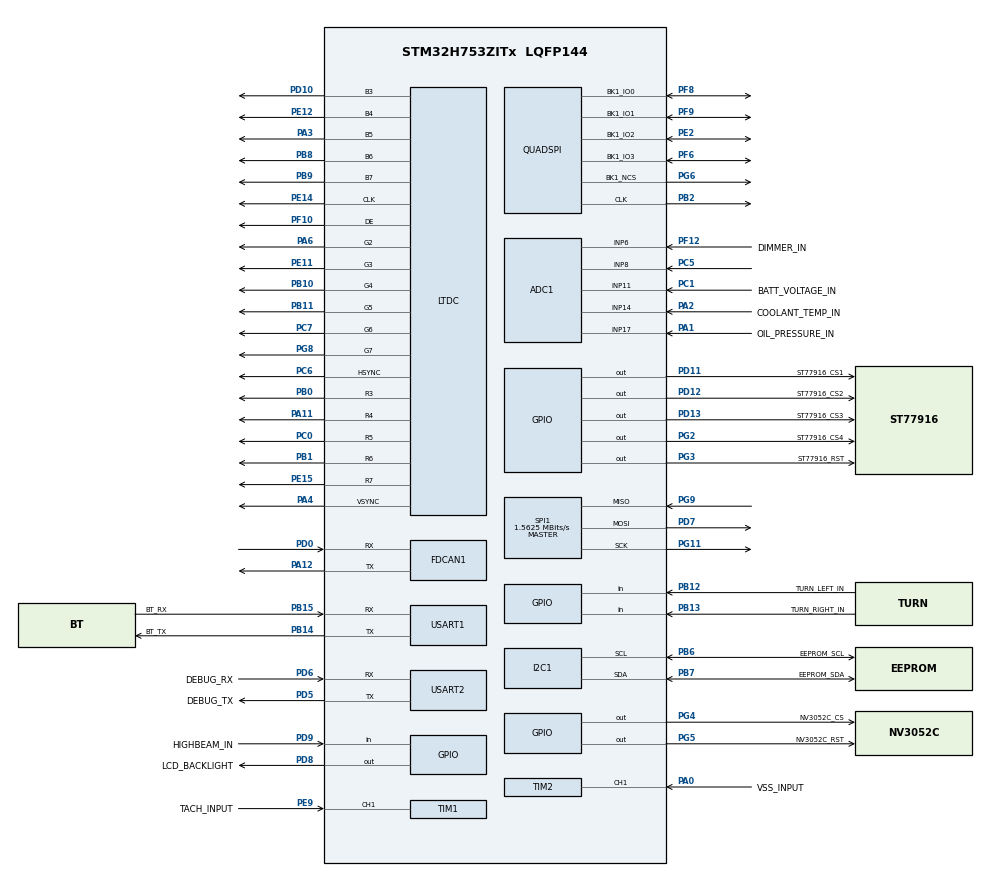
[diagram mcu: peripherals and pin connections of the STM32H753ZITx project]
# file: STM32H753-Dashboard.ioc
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ADC1.Channel-0\#ChannelRegularConversion=ADC_CHANNEL_6
ADC1.NbrOfConversionFlag=1
ADC1.OffsetNumber-0\#ChannelRegularConversion=ADC_OFFSET_NONE
ADC1.OffsetSignedSaturation-0\#ChannelRegularConversion=DISABLE
ADC1.Rank-0\#ChannelRegularConversion=1
ADC1.SamplingTime-0\#ChannelRegularConversion=ADC_SAMPLETIME_1CYCLE_5
ADC1.master=1
CORTEX_M7.default_mode_Activation=1
FDCAN1.AutoRetransmission=ENABLE
FDCAN1.CalculateBaudRateNominal=1000000
FDCAN1.CalculateTimeBitNominal=1000
FDCAN1.CalculateTimeQuantumNominal=100.0
FDCAN1.NominalPrescaler=5
FDCAN1.NominalTimeSeg1=7
FDCAN1.NominalTimeSeg2=2
FDCAN1.RxFifo0ElmtsNbr=8
FDCAN1.TxFifoQueueElmtsNbr=32
I2C1.Timing=0x00707CBB
LTDC.ActiveH=720
LTDC.ActiveW=720
LTDC.HBP=44
LTDC.HFP=46
LTDC.HSync=2
LTDC.Layers=0
LTDC.PixelFormat_L0=LTDC_PIXEL_FORMAT_RGB565
LTDC.VBP=16
LTDC.VFP=50
LTDC.VSync=5
LTDC.WindowX1_L0=719
LTDC.WindowY1_L0=719
Mcu.Family=STM32H7
Mcu.Name=STM32H753ZITx
Mcu.Package=LQFP144
NVIC.PriorityGroup=NVIC_PRIORITYGROUP_4
NVIC.TIM6_DAC_IRQn=true\:0\:0\:false\:false\:true\:true\:true\:true
PA0.GPIO_Label=VSS_INPUT
PA0.Signal=S_TIM2_CH1_ETR
PA1.GPIO_Label=OIL_PRESSURE_IN
PA1.Mode=IN17-Single-Ended
PA1.Signal=ADC1_INP17
PA11.Mode=RGB565
PA11.Signal=LTDC_R4
PA12.Mode=FDCAN_Activate
PA12.Signal=FDCAN1_TX
PA2.GPIO_Label=COOLANT_TEMP_IN
PA2.Signal=ADCx_INP14
PA3.Mode=RGB565
PA3.Signal=LTDC_B5
PA4.Mode=RGB565
PA4.Signal=LTDC_VSYNC
PA6.Mode=RGB565
PA6.Signal=LTDC_G2
PB0.Mode=RGB565
PB0.Signal=LTDC_R3
PB1.Mode=RGB565
PB1.Signal=LTDC_R6
PB10.Mode=RGB565
PB10.Signal=LTDC_G4
PB11.Mode=RGB565
PB11.Signal=LTDC_G5
PB12.GPIO_Label=TURN_LEFT_IN
PB12.Signal=GPIO_Input
PB13.GPIO_Label=TURN_RIGHT_IN
PB13.Signal=GPIO_Input
PB14.GPIO_Label=BT_TX
PB14.Mode=Asynchronous
PB14.Signal=USART1_TX
PB15.GPIO_Label=BT_RX
PB15.Mode=Asynchronous
PB15.Signal=USART1_RX
PB2.Mode=Single Bank 1
PB2.Signal=QUADSPI_CLK
PB6.GPIO_Label=EEPROM_SCL
PB6.Mode=I2C
PB6.Signal=I2C1_SCL
PB7.GPIO_Label=EEPROM_SDA
PB7.Mode=I2C
PB7.Signal=I2C1_SDA
PB8.Mode=RGB565
PB8.Signal=LTDC_B6
PB9.Mode=RGB565
PB9.Signal=LTDC_B7
PC0.Mode=RGB565
PC0.Signal=LTDC_R5
PC1.GPIO_Label=BATT_VOLTAGE_IN
PC1.Signal=ADCx_INP11
PC5.Signal=ADCx_INP8
PC6.Mode=RGB565
PC6.Signal=LTDC_HSYNC
PC7.Mode=RGB565
PC7.Signal=LTDC_G6
PD0.Mode=FDCAN_Activate
PD0.Signal=FDCAN1_RX
PD10.Mode=RGB565
PD10.Signal=LTDC_B3
PD11.GPIO_Label=ST77916_CS1
PD11.Signal=GPIO_Output
PD12.GPIO_Label=ST77916_CS2
PD12.Signal=GPIO_Output
PD13.GPIO_Label=ST77916_CS3
PD13.Signal=GPIO_Output
PD5.GPIO_Label=DEBUG_TX
PD5.Mode=Asynchronous
PD5.Signal=USART2_TX
PD6.GPIO_Label=DEBUG_RX
PD6.Mode=Asynchronous
PD6.Signal=USART2_RX
PD7.Mode=Full_Duplex_Master
PD7.Signal=SPI1_MOSI
PD8.GPIO_Label=LCD_BACKLIGHT
PD8.Signal=GPIO_Output
PD9.GPIO_Label=HIGHBEAM_IN
PD9.Signal=GPIO_Input
PE11.Mode=RGB565
PE11.Signal=LTDC_G3
PE12.Mode=RGB565
PE12.Signal=LTDC_B4
PE14.Mode=RGB565
PE14.Signal=LTDC_CLK
PE15.Mode=RGB565
PE15.Signal=LTDC_R7
PE2.Mode=Single Bank 1
PE2.Signal=QUADSPI_BK1_IO2
PE9.GPIO_Label=TACH_INPUT
PE9.Signal=S_TIM1_CH1
PF10.Mode=RGB565
PF10.Signal=LTDC_DE
PF12.GPIO_Label=DIMMER_IN
PF12.Mode=IN6-Single-Ended
PF12.Signal=ADC1_INP6
PF6.Mode=Single Bank 1
PF6.Signal=QUADSPI_BK1_IO3
PF8.Mode=Single Bank 1
PF8.Signal=QUADSPI_BK1_IO0
PF9.Mode=Single Bank 1
PF9.Signal=QUADSPI_BK1_IO1
PG11.Mode=Full_Duplex_Master
PG11.Signal=SPI1_SCK
PG2.GPIO_Label=ST77916_CS4
PG2.Signal=GPIO_Output
PG3.GPIO_Label=ST77916_RST
PG3.Signal=GPIO_Output
PG4.GPIO_Label=NV3052C_CS
PG4.Signal=GPIO_Output
PG5.GPIO_Label=NV3052C_RST
PG5.Signal=GPIO_Output
PG6.Mode=Single Bank 1
PG6.Signal=QUADSPI_BK1_NCS
PG8.Mode=RGB565
PG8.Signal=LTDC_G7
PG9.Mode=Full_Duplex_Master
PG9.Signal=SPI1_MISO
ProjectManager.HeapSize=0x200
ProjectManager.StackSize=0x400
ProjectManager.TargetToolchain=CMake
QUADSPI.ChipSelectHighTime=QSPI_CS_HIGH_TIME_2_CYCLE
QUADSPI.ClockPrescaler=4
QUADSPI.FifoThreshold=4
QUADSPI.FlashSize=22
QUADSPI.SampleShifting=QSPI_SAMPLE_SHIFTING_HALFCYCLE
RCC.ADCFreq_Value=80000000
RCC.APB1Freq_Value=32000000
RCC.APB2Freq_Value=32000000
RCC.APB3Freq_Value=64000000
RCC.APB4Freq_Value=64000000
RCC.CortexFreq_Value=64000000
RCC.D2PPRE1=RCC_APB1_DIV2
RCC.D2PPRE2=RCC_APB2_DIV2
RCC.DIVM1=4
RCC.DIVM2=4
RCC.DIVM3=1
RCC.DIVN1=9
RCC.DIVN2=10
RCC.DIVN3=4
RCC.DIVQ1=3
RCC.DIVR3=6
RCC.HCLKFreq_Value=64000000
RCC.PLL2FRACN=0
RCC.PLL3FRACN=0
RCC.PLLFRACN=3072
RCC.SYSCLKFreq_VALUE=64000000
RCC.USBFreq_Value=50000000
SH.ADCx_INP11.0=ADC1_INP11,IN11-Single-Ended
SH.ADCx_INP14.0=ADC1_INP14,IN14-Single-Ended
SH.ADCx_INP8.0=ADC1_INP8,IN8-Single-Ended
SH.S_TIM1_CH1.0=TIM1_CH1,Input_Capture1_from_TI1
SH.S_TIM2_CH1_ETR.0=TIM2_CH1,Input_Capture1_from_TI1
SPI1.BaudRatePrescaler=SPI_BAUDRATEPRESCALER_32
SPI1.CalculateBaudRate=1.5625 MBits/s
SPI1.DataSize=SPI_DATASIZE_8BIT
SPI1.Direction=SPI_DIRECTION_2LINES
SPI1.Mode=SPI_MODE_MASTER
SPI1.VirtualType=VM_MASTER
TIM1.Channel-Input_Capture1_from_TI1=TIM_CHANNEL_1
TIM2.Channel-Input_Capture1_from_TI1=TIM_CHANNEL_1
TIM6.Period=999
TIM6.Prescaler=63
USART1.VirtualMode-Asynchronous=VM_ASYNC
USART2.VirtualMode-Asynchronous=VM_ASYNC
VP_DMA2D_VS_DMA2D.Mode=DMA2D_Activate
VP_MEMORYMAP_VS_MEMORYMAP.Mode=CurAppReg
VP_TIM1_VS_ClockSourceINT.Mode=Internal
VP_TIM6_VS_ClockSourceINT.Mode=Enable_Timer
board=custom

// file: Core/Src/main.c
/* USER CODE BEGIN Header */
/**
  ******************************************************************************
  * @file           : main.c
  * @brief          : Main program body
  ******************************************************************************
  * @attention
  *
  * Copyright (c) 2026 STMicroelectronics.
  * All rights reserved.
  *
  * This software is licensed under terms that can be found in the LICENSE file
  * in the root directory of this software component.
  * If no LICENSE file comes with this software, it is provided AS-IS.
  *
  ******************************************************************************
  */
/* USER CODE END Header */
#include "main.h"

/* USER CODE BEGIN Includes */
#include "st77916.h"
#include "nv3052c.h"
#include "holley_can.h"
#include "sensors.h"
#include "inputs.h"
#include "config.h"
/* USER CODE END Includes */

ADC_HandleTypeDef hadc1;

DMA2D_HandleTypeDef hdma2d;

FDCAN_HandleTypeDef hfdcan1;

I2C_HandleTypeDef hi2c1;

LTDC_HandleTypeDef hltdc;

QSPI_HandleTypeDef hqspi;

SPI_HandleTypeDef hspi1;

TIM_HandleTypeDef htim1;
TIM_HandleTypeDef htim2;
TIM_HandleTypeDef htim6;

UART_HandleTypeDef huart1;
UART_HandleTypeDef huart2;

void SystemClock_Config(void);
static void MPU_Config(void);
static void MX_GPIO_Init(void);
static void MX_ADC1_Init(void);
static void MX_DMA2D_Init(void);
static void MX_FDCAN1_Init(void);
static void MX_I2C1_Init(void);
static void MX_LTDC_Init(void);
static void MX_QUADSPI_Init(void);
static void MX_SPI1_Init(void);
static void MX_TIM1_Init(void);
static void MX_TIM2_Init(void);
static void MX_TIM6_Init(void);
static void MX_USART1_UART_Init(void);
static void MX_USART2_UART_Init(void);

int main(void)
{

  /* MPU Configuration--------------------------------------------------------*/
  MPU_Config();

  /* MCU Configuration--------------------------------------------------------*/

  /* Reset of all peripherals, Initializes the Flash interface and the Systick. */
  HAL_Init();

  /* USER CODE BEGIN Init */
  /* Framebuffer RAM (AXI SRAM) as write-through: CPU writes reach RAM
   * immediately and in order, so LTDC scanout never sees stale or
   * half-flushed pixels and no per-frame cache maintenance is needed.
   * With write-back this raced the scanline and tore the moving needle.
   * Region 0 (background) is CubeMX-generated; this stacks region 1. */
  {
    MPU_Region_InitTypeDef r = {0};
    HAL_MPU_Disable();
    r.Enable           = MPU_REGION_ENABLE;
    r.Number           = MPU_REGION_NUMBER1;
    r.BaseAddress      = 0x24000000U;
    r.Size             = MPU_REGION_SIZE_512KB;
    r.TypeExtField     = MPU_TEX_LEVEL0;          /* TEX=0, C=1, B=0 = write-through */
    r.AccessPermission = MPU_REGION_FULL_ACCESS;
    r.DisableExec      = MPU_INSTRUCTION_ACCESS_DISABLE;
    r.IsShareable      = MPU_ACCESS_NOT_SHAREABLE;
    r.IsCacheable      = MPU_ACCESS_CACHEABLE;
    r.IsBufferable     = MPU_ACCESS_NOT_BUFFERABLE;
    HAL_MPU_ConfigRegion(&r);
    HAL_MPU_Enable(MPU_PRIVILEGED_DEFAULT);
  }
  /* CPU caches were never enabled; the Cortex-M7 is crippled without them and
   * cache-maintenance ops (used for LTDC framebuffer coherence) hard-fault if
   * executed while the D-cache is off. MPU_Config() has already run. */
  SCB_EnableICache();
  SCB_EnableDCache();
  /* USER CODE END Init */

  /* Configure the system clock */
  SystemClock_Config();

  /* Initialize all configured peripherals */
  MX_GPIO_Init();
  MX_ADC1_Init();
  MX_DMA2D_Init();
  MX_FDCAN1_Init();
  MX_I2C1_Init();
  MX_LTDC_Init();
  MX_QUADSPI_Init();
  MX_SPI1_Init();
  MX_TIM1_Init();
  MX_TIM2_Init();
  MX_TIM6_Init();
  MX_USART1_UART_Init();
  MX_USART2_UART_Init();
  /* USER CODE BEGIN 2 */
  HAL_GPIO_WritePin(LCD_BACKLIGHT_GPIO_Port, LCD_BACKLIGHT_Pin, GPIO_PIN_SET);
  ST77916_InitAll();
  ST77916_Fill(ST77916_DISPLAY_ALL, 0, 0, ST77916_WIDTH - 1, ST77916_HEIGHT - 1, 0x07E0); /* solid green */
  NV3052C_Init();
  Holley_CAN_Init();
  Config_Init();
  Sensors_Init();
  Inputs_Init();
  /* USER CODE END 2 */

  /* Infinite loop */
  while (1)
  {

    /* USER CODE BEGIN 3 */
    Holley_CAN_Update();
    Sensors_Update();
    Inputs_Update();
    Config_BtUpdate();
    NV3052C_Update();
  }
  /* USER CODE END 3 */
}

void SystemClock_Config(void)
{
  RCC_OscInitTypeDef RCC_OscInitStruct = {0};
  RCC_ClkInitTypeDef RCC_ClkInitStruct = {0};

  /** Supply configuration update enable
  */
  HAL_PWREx_ConfigSupply(PWR_LDO_SUPPLY);

  /** Configure the main internal regulator output voltage
  */
  __HAL_PWR_VOLTAGESCALING_CONFIG(PWR_REGULATOR_VOLTAGE_SCALE1);

  while(!__HAL_PWR_GET_FLAG(PWR_FLAG_VOSRDY)) {}

  /** Initializes the RCC Oscillators according to the specified parameters
  * in the RCC_OscInitTypeDef structure.
  */
  RCC_OscInitStruct.OscillatorType = RCC_OSCILLATORTYPE_HSI;
  RCC_OscInitStruct.HSIState = RCC_HSI_DIV1;
  RCC_OscInitStruct.HSICalibrationValue = RCC_HSICALIBRATION_DEFAULT;
  RCC_OscInitStruct.PLL.PLLState = RCC_PLL_ON;
  RCC_OscInitStruct.PLL.PLLSource = RCC_PLLSOURCE_HSI;
  RCC_OscInitStruct.PLL.PLLM = 4;      /* HSI64/4 = 16 MHz ref            */
  RCC_OscInitStruct.PLL.PLLN = 50;     /* VCO 800 MHz                     */
  RCC_OscInitStruct.PLL.PLLP = 2;      /* SYSCLK 400 MHz                  */
  RCC_OscInitStruct.PLL.PLLQ = 16;     /* pll1_q stays 50 MHz: FDCAN/SPI1
                                          bit timings unchanged           */
  RCC_OscInitStruct.PLL.PLLR = 2;
  RCC_OscInitStruct.PLL.PLLRGE = RCC_PLL1VCIRANGE_3;
  RCC_OscInitStruct.PLL.PLLVCOSEL = RCC_PLL1VCOWIDE;
  RCC_OscInitStruct.PLL.PLLFRACN = 0;
  if (HAL_RCC_OscConfig(&RCC_OscInitStruct) != HAL_OK)
  {
    Error_Handler();
  }

  /** Initializes the CPU, AHB and APB buses clocks
  */
  RCC_ClkInitStruct.ClockType = RCC_CLOCKTYPE_HCLK|RCC_CLOCKTYPE_SYSCLK
                              |RCC_CLOCKTYPE_PCLK1|RCC_CLOCKTYPE_PCLK2
                              |RCC_CLOCKTYPE_D3PCLK1|RCC_CLOCKTYPE_D1PCLK1;
  RCC_ClkInitStruct.SYSCLKSource = RCC_SYSCLKSOURCE_PLLCLK;   /* 400 MHz */
  RCC_ClkInitStruct.SYSCLKDivider = RCC_SYSCLK_DIV1;
  RCC_ClkInitStruct.AHBCLKDivider = RCC_HCLK_DIV2;             /* HCLK 200 */
  RCC_ClkInitStruct.APB3CLKDivider = RCC_APB3_DIV2;            /* 100 MHz  */
  RCC_ClkInitStruct.APB1CLKDivider = RCC_APB1_DIV2;            /* 100 MHz, timers 200 */
  RCC_ClkInitStruct.APB2CLKDivider = RCC_APB2_DIV2;            /* 100 MHz, timers 200 */
  RCC_ClkInitStruct.APB4CLKDivider = RCC_APB4_DIV2;            /* 100 MHz  */

  if (HAL_RCC_ClockConfig(&RCC_ClkInitStruct, FLASH_LATENCY_2) != HAL_OK)
  {
    Error_Handler();
  }

  /* RM0433: 185-210 MHz AXI at VOS1 needs WRHIGHFREQ=0b10 alongside WS=2 */
  MODIFY_REG(FLASH->ACR, FLASH_ACR_WRHIGHFREQ, FLASH_ACR_WRHIGHFREQ_1);
}

static void MX_ADC1_Init(void)
{

  ADC_MultiModeTypeDef multimode = {0};
  ADC_ChannelConfTypeDef sConfig = {0};

  /** Common config
  */
  hadc1.Instance = ADC1;
  hadc1.Init.ClockPrescaler = ADC_CLOCK_ASYNC_DIV2;
  hadc1.Init.Resolution = ADC_RESOLUTION_16B;
  hadc1.Init.ScanConvMode = ADC_SCAN_DISABLE;
  hadc1.Init.EOCSelection = ADC_EOC_SINGLE_CONV;
  hadc1.Init.LowPowerAutoWait = DISABLE;
  hadc1.Init.ContinuousConvMode = DISABLE;
  hadc1.Init.NbrOfConversion = 1;
  hadc1.Init.DiscontinuousConvMode = DISABLE;
  hadc1.Init.ExternalTrigConv = ADC_SOFTWARE_START;
  hadc1.Init.ExternalTrigConvEdge = ADC_EXTERNALTRIGCONVEDGE_NONE;
  hadc1.Init.ConversionDataManagement = ADC_CONVERSIONDATA_DR;
  hadc1.Init.Overrun = ADC_OVR_DATA_PRESERVED;
  hadc1.Init.LeftBitShift = ADC_LEFTBITSHIFT_NONE;
  hadc1.Init.OversamplingMode = DISABLE;
  hadc1.Init.Oversampling.Ratio = 1;
  if (HAL_ADC_Init(&hadc1) != HAL_OK)
  {
    Error_Handler();
  }

  /** Configure the ADC multi-mode
  */
  multimode.Mode = ADC_MODE_INDEPENDENT;
  if (HAL_ADCEx_MultiModeConfigChannel(&hadc1, &multimode) != HAL_OK)
  {
    Error_Handler();
  }

  /** Configure Regular Channel
  */
  sConfig.Channel = ADC_CHANNEL_6;
  sConfig.Rank = ADC_REGULAR_RANK_1;
  sConfig.SamplingTime = ADC_SAMPLETIME_1CYCLE_5;
  sConfig.SingleDiff = ADC_SINGLE_ENDED;
  sConfig.OffsetNumber = ADC_OFFSET_NONE;
  sConfig.Offset = 0;
  sConfig.OffsetSignedSaturation = DISABLE;
  if (HAL_ADC_ConfigChannel(&hadc1, &sConfig) != HAL_OK)
  {
    Error_Handler();
  }

}

static void MX_DMA2D_Init(void)
{

  hdma2d.Instance = DMA2D;
  hdma2d.Init.Mode = DMA2D_M2M;
  hdma2d.Init.ColorMode = DMA2D_OUTPUT_ARGB8888;
  hdma2d.Init.OutputOffset = 0;
  hdma2d.LayerCfg[1].InputOffset = 0;
  hdma2d.LayerCfg[1].InputColorMode = DMA2D_INPUT_ARGB8888;
  hdma2d.LayerCfg[1].AlphaMode = DMA2D_NO_MODIF_ALPHA;
  hdma2d.LayerCfg[1].InputAlpha = 0;
  hdma2d.LayerCfg[1].AlphaInverted = DMA2D_REGULAR_ALPHA;
  hdma2d.LayerCfg[1].RedBlueSwap = DMA2D_RB_REGULAR;
  hdma2d.LayerCfg[1].ChromaSubSampling = DMA2D_NO_CSS;
  if (HAL_DMA2D_Init(&hdma2d) != HAL_OK)
  {
    Error_Handler();
  }
  if (HAL_DMA2D_ConfigLayer(&hdma2d, 1) != HAL_OK)
  {
    Error_Handler();
  }

}

static void MX_FDCAN1_Init(void)
{

  hfdcan1.Instance = FDCAN1;
  hfdcan1.Init.FrameFormat = FDCAN_FRAME_CLASSIC;
  hfdcan1.Init.Mode = FDCAN_MODE_NORMAL;
  hfdcan1.Init.AutoRetransmission = ENABLE;
  hfdcan1.Init.TransmitPause = DISABLE;
  hfdcan1.Init.ProtocolException = DISABLE;
  hfdcan1.Init.NominalPrescaler = 5;
  hfdcan1.Init.NominalSyncJumpWidth = 1;
  hfdcan1.Init.NominalTimeSeg1 = 7;
  hfdcan1.Init.NominalTimeSeg2 = 2;
  hfdcan1.Init.DataPrescaler = 1;
  hfdcan1.Init.DataSyncJumpWidth = 1;
  hfdcan1.Init.DataTimeSeg1 = 1;
  hfdcan1.Init.DataTimeSeg2 = 1;
  hfdcan1.Init.MessageRAMOffset = 0;
  hfdcan1.Init.StdFiltersNbr = 0;
  hfdcan1.Init.ExtFiltersNbr = 0;
  hfdcan1.Init.RxFifo0ElmtsNbr = 8;
  hfdcan1.Init.RxFifo0ElmtSize = FDCAN_DATA_BYTES_8;
  hfdcan1.Init.RxFifo1ElmtsNbr = 0;
  hfdcan1.Init.RxFifo1ElmtSize = FDCAN_DATA_BYTES_8;
  hfdcan1.Init.RxBuffersNbr = 0;
  hfdcan1.Init.RxBufferSize = FDCAN_DATA_BYTES_8;
  hfdcan1.Init.TxEventsNbr = 0;
  hfdcan1.Init.TxBuffersNbr = 0;
  hfdcan1.Init.TxFifoQueueElmtsNbr = 32;
  hfdcan1.Init.TxFifoQueueMode = FDCAN_TX_FIFO_OPERATION;
  hfdcan1.Init.TxElmtSize = FDCAN_DATA_BYTES_8;
  if (HAL_FDCAN_Init(&hfdcan1) != HAL_OK)
  {
    Error_Handler();
  }

}

static void MX_I2C1_Init(void)
{

  hi2c1.Instance = I2C1;
  hi2c1.Init.Timing = 0x00707CBB;
  hi2c1.Init.OwnAddress1 = 0;
  hi2c1.Init.AddressingMode = I2C_ADDRESSINGMODE_7BIT;
  hi2c1.Init.DualAddressMode = I2C_DUALADDRESS_DISABLE;
  hi2c1.Init.OwnAddress2 = 0;
  hi2c1.Init.OwnAddress2Masks = I2C_OA2_NOMASK;
  hi2c1.Init.GeneralCallMode = I2C_GENERALCALL_DISABLE;
  hi2c1.Init.NoStretchMode = I2C_NOSTRETCH_DISABLE;
  if (HAL_I2C_Init(&hi2c1) != HAL_OK)
  {
    Error_Handler();
  }

  /** Configure Analogue filter
  */
  if (HAL_I2CEx_ConfigAnalogFilter(&hi2c1, I2C_ANALOGFILTER_ENABLE) != HAL_OK)
  {
    Error_Handler();
  }

  /** Configure Digital filter
  */
  if (HAL_I2CEx_ConfigDigitalFilter(&hi2c1, 0) != HAL_OK)
  {
    Error_Handler();
  }

}

static void MX_LTDC_Init(void)
{

  LTDC_LayerCfgTypeDef pLayerCfg = {0};

  hltdc.Instance = LTDC;
  hltdc.Init.HSPolarity = LTDC_HSPOLARITY_AL;
  hltdc.Init.VSPolarity = LTDC_VSPOLARITY_AL;
  hltdc.Init.DEPolarity = LTDC_DEPOLARITY_AL;
  hltdc.Init.PCPolarity = LTDC_PCPOLARITY_IIPC;
  hltdc.Init.HorizontalSync = 1;     /* HSPW=2 */
  hltdc.Init.VerticalSync = 4;       /* VSPW=5 */
  hltdc.Init.AccumulatedHBP = 45;    /* HBP=44 per manufacturer init code */
  hltdc.Init.AccumulatedVBP = 20;    /* VBP=16 per manufacturer init code */
  hltdc.Init.AccumulatedActiveW = 765;
  hltdc.Init.AccumulatedActiveH = 740;
  hltdc.Init.TotalWidth = 811;       /* HFP=46 per manufacturer init code */
  hltdc.Init.TotalHeigh = 790;       /* VFP=50 per manufacturer init code */
  hltdc.Init.Backcolor.Blue = 0;
  hltdc.Init.Backcolor.Green = 0;
  hltdc.Init.Backcolor.Red = 0;
  if (HAL_LTDC_Init(&hltdc) != HAL_OK)
  {
    Error_Handler();
  }
  pLayerCfg.WindowX0 = 0;
  pLayerCfg.WindowX1 = 719;
  pLayerCfg.WindowY0 = 0;
  pLayerCfg.WindowY1 = 719;
  pLayerCfg.PixelFormat = LTDC_PIXEL_FORMAT_RGB565;
  pLayerCfg.Alpha = 0;
  pLayerCfg.Alpha0 = 0;
  pLayerCfg.BlendingFactor1 = LTDC_BLENDING_FACTOR1_CA;
  pLayerCfg.BlendingFactor2 = LTDC_BLENDING_FACTOR2_CA;
  pLayerCfg.FBStartAdress = 0;
  pLayerCfg.ImageWidth = 0;
  pLayerCfg.ImageHeight = 0;
  pLayerCfg.Backcolor.Blue = 0;
  pLayerCfg.Backcolor.Green = 0;
  pLayerCfg.Backcolor.Red = 0;
  if (HAL_LTDC_ConfigLayer(&hltdc, &pLayerCfg, 0) != HAL_OK)
  {
    Error_Handler();
  }

}

static void MX_QUADSPI_Init(void)
{

  /* QUADSPI parameter configuration*/
  hqspi.Instance = QUADSPI;
  hqspi.Init.ClockPrescaler = 15;  /* D1HCLK 200 MHz / 16 = 12.5 MHz SCK (was 64/5 = 12.8) */
  hqspi.Init.FifoThreshold = 4;
  hqspi.Init.SampleShifting = QSPI_SAMPLE_SHIFTING_HALFCYCLE;
  hqspi.Init.FlashSize = 22;
  hqspi.Init.ChipSelectHighTime = QSPI_CS_HIGH_TIME_2_CYCLE;
  hqspi.Init.ClockMode = QSPI_CLOCK_MODE_3;
  hqspi.Init.FlashID = QSPI_FLASH_ID_1;
  hqspi.Init.DualFlash = QSPI_DUALFLASH_DISABLE;
  if (HAL_QSPI_Init(&hqspi) != HAL_OK)
  {
    Error_Handler();
  }

}

static void MX_SPI1_Init(void)
{

  /* SPI1 parameter configuration*/
  hspi1.Instance = SPI1;
  hspi1.Init.Mode = SPI_MODE_MASTER;
  hspi1.Init.Direction = SPI_DIRECTION_2LINES;
  hspi1.Init.DataSize = SPI_DATASIZE_8BIT;
  hspi1.Init.CLKPolarity = SPI_POLARITY_LOW;
  hspi1.Init.CLKPhase = SPI_PHASE_1EDGE;
  hspi1.Init.NSS = SPI_NSS_SOFT;
  hspi1.Init.BaudRatePrescaler = SPI_BAUDRATEPRESCALER_32;
  hspi1.Init.FirstBit = SPI_FIRSTBIT_MSB;
  hspi1.Init.TIMode = SPI_TIMODE_DISABLE;
  hspi1.Init.CRCCalculation = SPI_CRCCALCULATION_DISABLE;
  hspi1.Init.CRCPolynomial = 0x0;
  hspi1.Init.NSSPMode = SPI_NSS_PULSE_ENABLE;
  hspi1.Init.NSSPolarity = SPI_NSS_POLARITY_LOW;
  hspi1.Init.FifoThreshold = SPI_FIFO_THRESHOLD_01DATA;
  hspi1.Init.TxCRCInitializationPattern = SPI_CRC_INITIALIZATION_ALL_ZERO_PATTERN;
  hspi1.Init.RxCRCInitializationPattern = SPI_CRC_INITIALIZATION_ALL_ZERO_PATTERN;
  hspi1.Init.MasterSSIdleness = SPI_MASTER_SS_IDLENESS_00CYCLE;
  hspi1.Init.MasterInterDataIdleness = SPI_MASTER_INTERDATA_IDLENESS_00CYCLE;
  hspi1.Init.MasterReceiverAutoSusp = SPI_MASTER_RX_AUTOSUSP_DISABLE;
  hspi1.Init.MasterKeepIOState = SPI_MASTER_KEEP_IO_STATE_DISABLE;
  hspi1.Init.IOSwap = SPI_IO_SWAP_DISABLE;
  if (HAL_SPI_Init(&hspi1) != HAL_OK)
  {
    Error_Handler();
  }

}

static void MX_TIM1_Init(void)
{

  TIM_ClockConfigTypeDef sClockSourceConfig = {0};
  TIM_MasterConfigTypeDef sMasterConfig = {0};
  TIM_IC_InitTypeDef sConfigIC = {0};

  htim1.Instance = TIM1;
  htim1.Init.Prescaler = 0;
  htim1.Init.CounterMode = TIM_COUNTERMODE_UP;
  htim1.Init.Period = 65535;
  htim1.Init.ClockDivision = TIM_CLOCKDIVISION_DIV1;
  htim1.Init.RepetitionCounter = 0;
  htim1.Init.AutoReloadPreload = TIM_AUTORELOAD_PRELOAD_DISABLE;
  if (HAL_TIM_Base_Init(&htim1) != HAL_OK)
  {
    Error_Handler();
  }
  sClockSourceConfig.ClockSource = TIM_CLOCKSOURCE_INTERNAL;
  if (HAL_TIM_ConfigClockSource(&htim1, &sClockSourceConfig) != HAL_OK)
  {
    Error_Handler();
  }
  if (HAL_TIM_IC_Init(&htim1) != HAL_OK)
  {
    Error_Handler();
  }
  sMasterConfig.MasterOutputTrigger = TIM_TRGO_RESET;
  sMasterConfig.MasterOutputTrigger2 = TIM_TRGO2_RESET;
  sMasterConfig.MasterSlaveMode = TIM_MASTERSLAVEMODE_DISABLE;
  if (HAL_TIMEx_MasterConfigSynchronization(&htim1, &sMasterConfig) != HAL_OK)
  {
    Error_Handler();
  }
  sConfigIC.ICPolarity = TIM_INPUTCHANNELPOLARITY_RISING;
  sConfigIC.ICSelection = TIM_ICSELECTION_DIRECTTI;
  sConfigIC.ICPrescaler = TIM_ICPSC_DIV1;
  sConfigIC.ICFilter = 0;
  if (HAL_TIM_IC_ConfigChannel(&htim1, &sConfigIC, TIM_CHANNEL_1) != HAL_OK)
  {
    Error_Handler();
  }

}

static void MX_TIM2_Init(void)
{

  TIM_MasterConfigTypeDef sMasterConfig = {0};
  TIM_IC_InitTypeDef sConfigIC = {0};

  htim2.Instance = TIM2;
  htim2.Init.Prescaler = 0;
  htim2.Init.CounterMode = TIM_COUNTERMODE_UP;
  htim2.Init.Period = 4294967295;
  htim2.Init.ClockDivision = TIM_CLOCKDIVISION_DIV1;
  htim2.Init.AutoReloadPreload = TIM_AUTORELOAD_PRELOAD_DISABLE;
  if (HAL_TIM_IC_Init(&htim2) != HAL_OK)
  {
    Error_Handler();
  }
  sMasterConfig.MasterOutputTrigger = TIM_TRGO_RESET;
  sMasterConfig.MasterSlaveMode = TIM_MASTERSLAVEMODE_DISABLE;
  if (HAL_TIMEx_MasterConfigSynchronization(&htim2, &sMasterConfig) != HAL_OK)
  {
    Error_Handler();
  }
  sConfigIC.ICPolarity = TIM_INPUTCHANNELPOLARITY_RISING;
  sConfigIC.ICSelection = TIM_ICSELECTION_DIRECTTI;
  sConfigIC.ICPrescaler = TIM_ICPSC_DIV1;
  sConfigIC.ICFilter = 0;
  if (HAL_TIM_IC_ConfigChannel(&htim2, &sConfigIC, TIM_CHANNEL_1) != HAL_OK)
  {
    Error_Handler();
  }

}

static void MX_TIM6_Init(void)
{

  TIM_MasterConfigTypeDef sMasterConfig = {0};

  htim6.Instance = TIM6;
  htim6.Init.Prescaler = 63;
  htim6.Init.CounterMode = TIM_COUNTERMODE_UP;
  htim6.Init.Period = 999;
  htim6.Init.AutoReloadPreload = TIM_AUTORELOAD_PRELOAD_DISABLE;
  if (HAL_TIM_Base_Init(&htim6) != HAL_OK)
  {
    Error_Handler();
  }
  sMasterConfig.MasterOutputTrigger = TIM_TRGO_RESET;
  sMasterConfig.MasterSlaveMode = TIM_MASTERSLAVEMODE_DISABLE;
  if (HAL_TIMEx_MasterConfigSynchronization(&htim6, &sMasterConfig) != HAL_OK)
  {
    Error_Handler();
  }

}

static void MX_USART1_UART_Init(void)
{

  huart1.Instance = USART1;
  huart1.Init.BaudRate = 115200;
  huart1.Init.WordLength = UART_WORDLENGTH_8B;
  huart1.Init.StopBits = UART_STOPBITS_1;
  huart1.Init.Parity = UART_PARITY_NONE;
  huart1.Init.Mode = UART_MODE_TX_RX;
  huart1.Init.HwFlowCtl = UART_HWCONTROL_NONE;
  huart1.Init.OverSampling = UART_OVERSAMPLING_16;
  huart1.Init.OneBitSampling = UART_ONE_BIT_SAMPLE_DISABLE;
  huart1.Init.ClockPrescaler = UART_PRESCALER_DIV1;
  huart1.AdvancedInit.AdvFeatureInit = UART_ADVFEATURE_NO_INIT;
  if (HAL_UART_Init(&huart1) != HAL_OK)
  {
    Error_Handler();
  }
  if (HAL_UARTEx_SetTxFifoThreshold(&huart1, UART_TXFIFO_THRESHOLD_1_8) != HAL_OK)
  {
    Error_Handler();
  }
  if (HAL_UARTEx_SetRxFifoThreshold(&huart1, UART_RXFIFO_THRESHOLD_1_8) != HAL_OK)
  {
    Error_Handler();
  }
  if (HAL_UARTEx_DisableFifoMode(&huart1) != HAL_OK)
  {
    Error_Handler();
  }

}

static void MX_USART2_UART_Init(void)
{

  huart2.Instance = USART2;
  huart2.Init.BaudRate = 115200;
  huart2.Init.WordLength = UART_WORDLENGTH_8B;
  huart2.Init.StopBits = UART_STOPBITS_1;
  huart2.Init.Parity = UART_PARITY_NONE;
  huart2.Init.Mode = UART_MODE_TX_RX;
  huart2.Init.HwFlowCtl = UART_HWCONTROL_NONE;
  huart2.Init.OverSampling = UART_OVERSAMPLING_16;
  huart2.Init.OneBitSampling = UART_ONE_BIT_SAMPLE_DISABLE;
  huart2.Init.ClockPrescaler = UART_PRESCALER_DIV1;
  huart2.AdvancedInit.AdvFeatureInit = UART_ADVFEATURE_NO_INIT;
  if (HAL_UART_Init(&huart2) != HAL_OK)
  {
    Error_Handler();
  }
  if (HAL_UARTEx_SetTxFifoThreshold(&huart2, UART_TXFIFO_THRESHOLD_1_8) != HAL_OK)
  {
    Error_Handler();
  }
  if (HAL_UARTEx_SetRxFifoThreshold(&huart2, UART_RXFIFO_THRESHOLD_1_8) != HAL_OK)
  {
    Error_Handler();
  }
  if (HAL_UARTEx_DisableFifoMode(&huart2) != HAL_OK)
  {
    Error_Handler();
  }

}

static void MX_GPIO_Init(void)
{
  GPIO_InitTypeDef GPIO_InitStruct = {0};

  /* GPIO Ports Clock Enable */
  __HAL_RCC_GPIOE_CLK_ENABLE();
  __HAL_RCC_GPIOF_CLK_ENABLE();
  __HAL_RCC_GPIOC_CLK_ENABLE();
  __HAL_RCC_GPIOA_CLK_ENABLE();
  __HAL_RCC_GPIOB_CLK_ENABLE();
  __HAL_RCC_GPIOD_CLK_ENABLE();
  __HAL_RCC_GPIOG_CLK_ENABLE();

  /*Configure GPIO pin Output Level */
  HAL_GPIO_WritePin(GPIOD, LCD_BACKLIGHT_Pin|ST77916_CS1_Pin|ST77916_CS2_Pin|ST77916_CS3_Pin, GPIO_PIN_RESET);

  /*Configure GPIO pin Output Level */
  HAL_GPIO_WritePin(GPIOG, ST77916_CS4_Pin|ST77916_RST_Pin|NV3052C_CS_Pin|NV3052C_RST_Pin, GPIO_PIN_RESET);

  /*Configure GPIO pins : TURN_LEFT_IN_Pin TURN_RIGHT_IN_Pin */
  GPIO_InitStruct.Pin = TURN_LEFT_IN_Pin|TURN_RIGHT_IN_Pin;
  GPIO_InitStruct.Mode = GPIO_MODE_INPUT;
  GPIO_InitStruct.Pull = GPIO_NOPULL;
  HAL_GPIO_Init(GPIOB, &GPIO_InitStruct);

  /*Configure GPIO pins : LCD_BACKLIGHT_Pin ST77916_CS1_Pin ST77916_CS2_Pin ST77916_CS3_Pin */
  GPIO_InitStruct.Pin = LCD_BACKLIGHT_Pin|ST77916_CS1_Pin|ST77916_CS2_Pin|ST77916_CS3_Pin;
  GPIO_InitStruct.Mode = GPIO_MODE_OUTPUT_PP;
  GPIO_InitStruct.Pull = GPIO_NOPULL;
  GPIO_InitStruct.Speed = GPIO_SPEED_FREQ_LOW;
  HAL_GPIO_Init(GPIOD, &GPIO_InitStruct);

  /*Configure GPIO pin : HIGHBEAM_IN_Pin */
  GPIO_InitStruct.Pin = HIGHBEAM_IN_Pin;
  GPIO_InitStruct.Mode = GPIO_MODE_INPUT;
  GPIO_InitStruct.Pull = GPIO_NOPULL;
  HAL_GPIO_Init(HIGHBEAM_IN_GPIO_Port, &GPIO_InitStruct);

  /*Configure GPIO pins : ST77916_CS4_Pin ST77916_RST_Pin NV3052C_CS_Pin NV3052C_RST_Pin */
  GPIO_InitStruct.Pin = ST77916_CS4_Pin|ST77916_RST_Pin|NV3052C_CS_Pin|NV3052C_RST_Pin;
  GPIO_InitStruct.Mode = GPIO_MODE_OUTPUT_PP;
  GPIO_InitStruct.Pull = GPIO_NOPULL;
  GPIO_InitStruct.Speed = GPIO_SPEED_FREQ_LOW;
  HAL_GPIO_Init(GPIOG, &GPIO_InitStruct);

}

 /* MPU Configuration */

void MPU_Config(void)
{
  MPU_Region_InitTypeDef MPU_InitStruct = {0};

  /* Disables the MPU */
  HAL_MPU_Disable();

  /** Initializes and configures the Region and the memory to be protected
  */
  MPU_InitStruct.Enable = MPU_REGION_ENABLE;
  MPU_InitStruct.Number = MPU_REGION_NUMBER0;
  MPU_InitStruct.BaseAddress = 0x0;
  MPU_InitStruct.Size = MPU_REGION_SIZE_4GB;
  MPU_InitStruct.SubRegionDisable = 0x87;
  MPU_InitStruct.TypeExtField = MPU_TEX_LEVEL0;
  MPU_InitStruct.AccessPermission = MPU_REGION_NO_ACCESS;
  MPU_InitStruct.DisableExec = MPU_INSTRUCTION_ACCESS_DISABLE;
  MPU_InitStruct.IsShareable = MPU_ACCESS_SHAREABLE;
  MPU_InitStruct.IsCacheable = MPU_ACCESS_NOT_CACHEABLE;
  MPU_InitStruct.IsBufferable = MPU_ACCESS_NOT_BUFFERABLE;

  HAL_MPU_ConfigRegion(&MPU_InitStruct);
  /* Enables the MPU */
  HAL_MPU_Enable(MPU_PRIVILEGED_DEFAULT);

}

void Error_Handler(void)
{
  __disable_irq();
  while (1)
  {
  }
}
